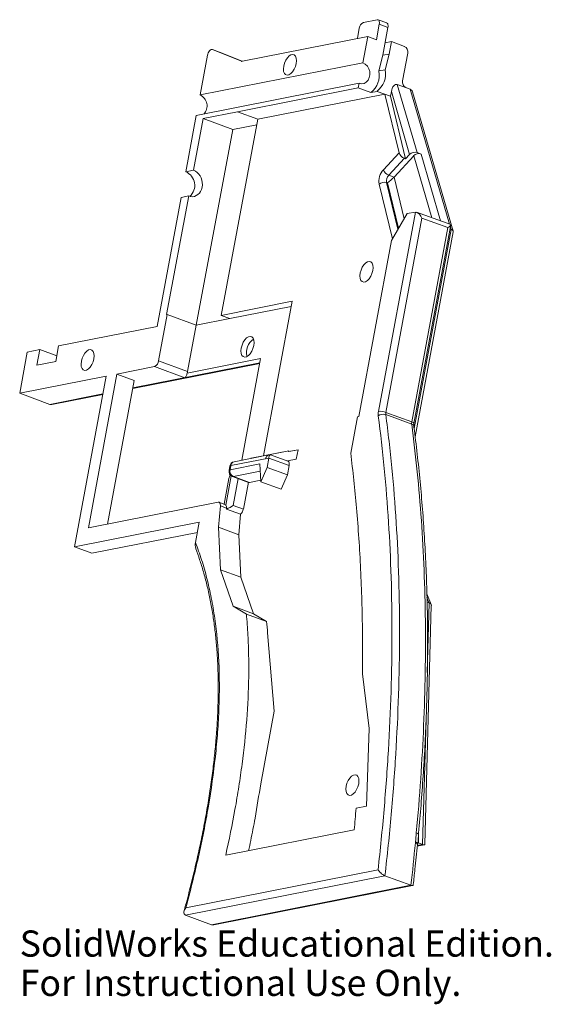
# Model space of a CAD drawing. Units: millimetres. Extents: x -5 to 93, y -110 to 72.
import ezdxf

# ---------------------------------------------------------------- set-up
doc = ezdxf.new("R2010")
doc.units = ezdxf.units.MM
doc.styles.add('SLDTEXTSTYLE0', font='TXT', dxfattribs={"width": 0.7})

msp = doc.modelspace()

# ---------------------------------------------------------------- linework, layer by layer
at = {"color": 7, "linetype": 'Continuous', "lineweight": 15}
for p, q in [((58.5, 71.07), (61.04, 71.56)), ((62.81, 70.96), (61.21, 71.55)), ((57.74, 70.01), (57.38, 68.07)), ((61.44, 70.72), (60.91, 67.87)), ((63.04, 70.13), (61.44, 70.72)), ((63.04, 70.13), (62.08, 64.99)), ((36.17, 63.88), (59.32, 68.46)), ((58.42, 63.61), (59.32, 68.46)), ((60.91, 67.87), (59.32, 68.46)), ((62.51, 67.29), (63.66, 67.51)), ((63.24, 65.22), (63.66, 67.51)), ((66.06, 66.64), (63.66, 67.51)), ((30.63, 66.04), (36, 63.9)), ((31.96, 65.55), (30.63, 66.04)), ((31.96, 65.55), (36.15, 63.88)), ((28.34, 57.67), (29.7, 64.99)), ((58.42, 63.61), (28.34, 57.67)), ((61.36, 62.1), (62.08, 64.99)), ((62.08, 64.99), (63.24, 65.22)), ((62.52, 62.32), (63.24, 65.22)), ((66.68, 65.39), (65.72, 60.26)), ((61.36, 62.1), (62.52, 62.32)), ((27.64, 53.88), (57.71, 59.82)), ((57.55, 58.96), (35.26, 54.56)), ((57.55, 58.96), (57.71, 59.82)), ((59.86, 58.11), (57.55, 58.96)), ((59.86, 58.11), (61.02, 58.34)), ((61.02, 58.34), (63.49, 57.43)), ((63.66, 58.31), (63.49, 57.43)), ((67.04, 46.71), (63.66, 58.31)), ((64.75, 59.6), (67.14, 58.73)), ((64.75, 59.6), (68.42, 47.04)), ((74.42, 33.81), (67.14, 58.73)), ((75.07, 32.56), (67.56, 58.26)), ((62.46, 57.81), (39.01, 53.18)), ((65.09, 47.01), (62.46, 57.81)), ((63.49, 57.43), (66.3, 45.9)), ((28.92, 53.31), (35.26, 54.56)), ((35.26, 54.56), (39.01, 53.18)), ((25.71, 43.49), (27.64, 53.88)), ((28.92, 53.31), (27.14, 43.77)), ((34.39, 51.31), (28.92, 53.31)), ((39.01, 53.18), (32.26, 17)), ((27.66, 15.2), (34.39, 51.31)), ((34.39, 51.31), (38.82, 52.17)), ((62.2, 43.88), (65.09, 47.01)), ((66.06, 45.99), (63.18, 42.86)), ((64.15, 42.51), (67.78, 46.44)), ((66.06, 45.99), (66.3, 45.9)), ((67.04, 46.71), (66.3, 45.9)), ((71.11, 35.02), (67.78, 46.44)), ((68.42, 47.04), (69.15, 46.77)), ((69.15, 46.77), (72.76, 34.42)), ((27.14, 43.77), (25.71, 43.49)), ((63.18, 42.86), (64.15, 42.51)), ((64.15, 42.51), (66.03, 34.81)), ((63.85, 31.13), (61.4, 41.18)), ((62.95, 41.45), (62.78, 41.52)), ((62.78, 41.52), (64.88, 32.88)), ((65, 33.07), (62.95, 41.45)), ((20.4, 14.95), (24.83, 38.74)), ((26.25, 39.03), (22.17, 17.14)), ((24.83, 38.74), (26.25, 39.03)), ((61.26, -0.72), (68.1, 36.07)), ((69.3, 34.95), (62.64, -0.9)), ((63.67, 30.82), (66.6, 35.78)), ((66.6, 35.78), (68.1, 36.07)), ((74.61, 33.74), (68.31, 36.05)), ((74.09, 33.19), (69.3, 34.95)), ((67.42, -2.66), (74.09, 33.19)), ((67.83, -2.96), (74.64, 33.69)), ((67.86, -3.9), (74.69, 32.87)), ((74.69, 32.87), (74.5, 32.94)), ((74.69, 32.87), (74.57, 33.3)), ((68.04, -5.39), (75.07, 32.44)), ((63.67, 30.82), (57.63, -1.66)), ((32.26, 17), (45.34, 19.59)), ((33.87, 16.41), (45.16, 18.64)), ((45.34, 19.59), (40.04, -8.9)), ((22.29, 17.16), (20.7, 8.61)), ((22.17, 17.14), (22.29, 17.16)), ((27.65, 15.2), (22.29, 17.16)), ((33.87, 16.41), (27.65, 15.2)), ((32.26, 17), (33.87, 16.41)), ((2.23, 11.36), (20.4, 14.95)), ((27.65, 15.2), (26.06, 6.64)), ((1.7, 8.51), (2.23, 11.36)), ((-4.95, 2.62), (-3.54, 10.22)), ((-3.54, 10.22), (-1.23, 10.67)), ((-1.76, 7.83), (-1.23, 10.67)), ((1.89, 9.53), (-1.23, 10.67)), ((1.7, 8.51), (-1.76, 7.83)), ((19.95, 7.54), (13.01, 6.17)), ((15.92, 3.49), (39.37, 8.12)), ((15.94, 3.6), (39.39, 8.23)), ((25.53, 5.49), (19.95, 7.54)), ((20.7, 8.61), (26.06, 6.64)), ((25.98, 6.35), (39.53, 9.02)), ((39.53, 9.02), (36.05, -9.74)), ((11.03, 5.78), (-4.95, 2.62)), ((11.03, 5.78), (5.17, -25.73)), ((7.73, -22.21), (13.01, 6.17)), ((16.2, 5), (13.01, 6.17)), ((11.27, -21.51), (16.2, 5)), ((-4.95, 2.62), (0.63, 0.58)), ((0.63, 0.58), (10.42, 2.51)), ((1, 0.54), (10.4, 2.4)), ((56.15, -8.42), (57.4, -1.71)), ((57.4, -1.71), (57.63, -1.66)), ((67.41, -3.08), (62.62, -1.32)), ((62.64, -0.9), (67.42, -2.66)), ((41.31, -8.7), (34.64, -10.02)), ((44.73, -7.99), (37.76, -9.36)), ((40.04, -8.9), (44.73, -7.97)), ((40.07, -8.91), (40.04, -8.9)), ((44.55, -9.88), (41.35, -8.71)), ((44.7, -8.13), (46.43, -7.79)), ((44.73, -7.97), (44.7, -8.13)), ((44.7, -8.13), (44.73, -8.14)), ((46.43, -7.8), (44.73, -8.14)), ((46.43, -7.79), (46.11, -9.53)), ((33.85, -10.82), (33.7, -11.61)), ((33.89, -11.5), (39.4, -10.41)), ((34.03, -10.71), (33.89, -11.5)), ((41.03, -9.33), (34.03, -10.71)), ((37.75, -9.41), (37.76, -9.36)), ((39.4, -10.41), (39.58, -13.71)), ((40.71, -11.07), (41.03, -9.33)), ((44.78, -10.7), (41.03, -9.33)), ((44.78, -10.7), (44.46, -12.44)), ((46.11, -9.53), (44.47, -9.85)), ((33.08, -18.01), (34.09, -12.6)), ((39.47, -11.76), (34.51, -12.74)), ((39.58, -13.71), (40.71, -11.07)), ((40.71, -11.07), (44.46, -12.44)), ((44.46, -12.44), (43.33, -15.08)), ((32.77, -17.83), (33.65, -13.13)), ((34.34, -12.73), (37.29, -13.82)), ((35.4, -13.12), (34.48, -18.07)), ((34.51, -12.74), (37.46, -13.83)), ((36.34, -18.75), (37.26, -13.8)), ((39.56, -13.41), (37.46, -13.83)), ((39.58, -13.71), (43.33, -15.08)), ((31.67, -17.48), (7.73, -22.21)), ((32.1, -18.17), (31.74, -22.11)), ((32.93, -17.89), (31.84, -17.49)), ((33.25, -18.59), (32.1, -18.17)), ((34.48, -18.07), (36.34, -18.75)), ((33.24, -18.74), (35.83, -19.69)), ((35.83, -19.69), (35.49, -23.49)), ((5.17, -25.73), (28.2, -21.18)), ((28.2, -21.18), (27.51, -24.9)), ((8.36, -26.9), (27.85, -23.05)), ((31.74, -22.11), (32.12, -29.96)), ((35.49, -23.49), (31.74, -22.11)), ((35.49, -23.49), (35.87, -31.33)), ((8.36, -26.9), (5.17, -25.73)), ((32.12, -29.96), (34.47, -36.68)), ((35.87, -31.33), (32.12, -29.96)), ((35.87, -31.33), (38.22, -38.05)), ((71.02, -36.36), (70.23, -34.41)), ((70.65, -36.05), (70.24, -35.04)), ((70.65, -36.05), (70.26, -35.91)), ((70.3, -48.88), (70.65, -36.05)), ((34.47, -36.68), (36.89, -38.12)), ((38.22, -38.05), (34.47, -36.68)), ((36.89, -38.12), (40.63, -39.49)), ((38.22, -38.05), (40.63, -39.49)), ((69.85, -80.56), (71.04, -36.52)), ((40.81, -41.61), (42.03, -56.03)), ((59.59, -59.24), (58.32, -49.13)), ((42.03, -56.03), (39.54, -69.43)), ((69.44, -80.65), (70.07, -57.58)), ((59.06, -73.59), (59.59, -59.24)), ((57.15, -73.96), (59.06, -73.59)), ((33.08, -82.64), (56.81, -77.95)), ((68.52, -80.56), (68.67, -78.84)), ((68.7, -78.32), (68.65, -80.36)), ((68.44, -80.96), (69.74, -80.7)), ((68.45, -80.85), (69.44, -80.65)), ((68.65, -80.36), (68.53, -80.38)), ((69.44, -80.65), (68.65, -80.36)), ((25.73, -92.32), (61.21, -85.31)), ((62.48, -86.42), (25.68, -93.69)), ((62.48, -86.42), (67.27, -88.18)), ((30.47, -95.45), (67.27, -88.18)), ((30.91, -95.47), (67.57, -88.22)), ((25.68, -93.69), (30.47, -95.45))]:
    msp.add_line(p, q, dxfattribs=at)
at = {"color": 7, "linetype": 'Continuous', "lineweight": 15, "flags": 128}
for points in [[(61.44, 70.72), (61.47, 70.9), (61.47, 71.07), (61.44, 71.23), (61.4, 71.36), (61.33, 71.46), (61.25, 71.53), (61.15, 71.56), (61.04, 71.56)], [(62.81, 70.96), (62.85, 70.94), (62.93, 70.87), (62.99, 70.77), (63.04, 70.64), (63.06, 70.49), (63.06, 70.32), (63.04, 70.13)], [(30.63, 66.04), (30.51, 66.06), (30.37, 66.03), (30.23, 65.94), (30.09, 65.81), (29.96, 65.64), (29.85, 65.44), (29.76, 65.22), (29.7, 64.99)], [(46.1, 63.47), (46.15, 63.99), (46.11, 64.46), (45.97, 64.82), (45.75, 65.06), (45.46, 65.15), (45.13, 65.09), (44.79, 64.87), (44.46, 64.53), (44.17, 64.07), (43.94, 63.56), (43.79, 63.01), (43.74, 62.49), (43.78, 62.02), (43.92, 61.66), (44.15, 61.42), (44.43, 61.33), (44.76, 61.39), (45.1, 61.61), (45.43, 61.95), (45.73, 62.4), (45.95, 62.92), (46.1, 63.47)], [(58.42, 63.61), (58.85, 63.37), (59.23, 63), (59.5, 62.52), (59.66, 61.97), (59.7, 61.41), (59.59, 60.87), (59.37, 60.39), (59.04, 60.03), (58.63, 59.8), (58.18, 59.73), (57.71, 59.82)], [(63.66, 58.31), (63.73, 58.61), (63.83, 58.89), (63.95, 59.14), (64.1, 59.35), (64.26, 59.5), (64.42, 59.6), (64.59, 59.63), (64.75, 59.6)], [(26.25, 39.03), (26.61, 38.93), (26.97, 38.9), (27.32, 38.96), (27.65, 39.09), (27.96, 39.29), (28.23, 39.56), (28.45, 39.88), (28.61, 40.25), (28.72, 40.65), (28.77, 41.08), (28.75, 41.52), (28.67, 41.95), (28.53, 42.37), (28.34, 42.75), (28.09, 43.1), (27.8, 43.39), (27.48, 43.61), (27.14, 43.77)], [(74.09, 33.19), (74.25, 33.3), (74.39, 33.41), (74.5, 33.5), (74.58, 33.59), (74.63, 33.65), (74.64, 33.7), (74.62, 33.73), (74.61, 33.74)], [(74.69, 32.87), (74.82, 32.82), (74.93, 32.75), (75.01, 32.67), (75.06, 32.59), (75.08, 32.5), (75.07, 32.44)], [(57.92, 24.82), (58.07, 25.36), (58.3, 25.88), (58.59, 26.33), (58.92, 26.68), (59.26, 26.89), (59.59, 26.96), (59.88, 26.87), (60.1, 26.63), (60.24, 26.26), (60.28, 25.8), (60.23, 25.27), (60.08, 24.73), (59.86, 24.21), (59.56, 23.76), (59.23, 23.41), (58.89, 23.2), (58.56, 23.13), (58.28, 23.22), (58.05, 23.46), (57.91, 23.83), (57.87, 24.29), (57.92, 24.82)], [(38.26, 11.43), (38.11, 10.88), (37.89, 10.37), (37.6, 9.91), (37.26, 9.57), (36.92, 9.35), (36.59, 9.29), (36.31, 9.38), (36.08, 9.62), (35.95, 9.98), (35.9, 10.45), (35.95, 10.97), (36.1, 11.52), (36.33, 12.04), (36.62, 12.49), (36.95, 12.83), (37.29, 13.05), (37.62, 13.11), (37.91, 13.02), (38.13, 12.78), (38.27, 12.42), (38.31, 11.95), (38.26, 11.43)], [(8.75, 8.99), (8.8, 9.51), (8.75, 9.98), (8.61, 10.34), (8.39, 10.58), (8.11, 10.67), (7.78, 10.61), (7.43, 10.39), (7.1, 10.04), (6.81, 9.59), (6.58, 9.08), (6.44, 8.53), (6.39, 8.01), (6.43, 7.54), (6.57, 7.17), (6.79, 6.94), (7.08, 6.85), (7.41, 6.91), (7.75, 7.13), (8.08, 7.47), (8.37, 7.92), (8.6, 8.44), (8.75, 8.99)], [(67.42, -2.66), (67.57, -2.72), (67.69, -2.78), (67.77, -2.84), (67.82, -2.9), (67.83, -2.95), (67.83, -2.95)], [(41.03, -9.33), (41.07, -9.15), (41.12, -9), (41.17, -8.87), (41.22, -8.78), (41.28, -8.72), (41.33, -8.7), (41.35, -8.71)], [(44.55, -9.88), (44.59, -9.9), (44.67, -9.96), (44.74, -10.06), (44.78, -10.19), (44.81, -10.35), (44.81, -10.52), (44.78, -10.7)], [(34.51, -12.74), (34.4, -12.75), (34.34, -12.73)], [(32.1, -18.17), (32.1, -18.01), (32.09, -17.87), (32.05, -17.74), (32.01, -17.63), (31.94, -17.55), (31.86, -17.5), (31.77, -17.48), (31.67, -17.48)], [(33.24, -18.74), (33.24, -18.66), (33.25, -18.59)], [(55.32, -69.9), (55.46, -69.35), (55.69, -68.84), (55.98, -68.38), (56.31, -68.04), (56.66, -67.82), (56.99, -67.76), (57.27, -67.85), (57.49, -68.09), (57.63, -68.45), (57.68, -68.92), (57.63, -69.44), (57.48, -69.99), (57.25, -70.51), (56.96, -70.96), (56.63, -71.3), (56.29, -71.52), (55.96, -71.58), (55.67, -71.49), (55.45, -71.25), (55.31, -70.89), (55.27, -70.42), (55.32, -69.9)], [(68.27, -78.49), (68.41, -78.55), (68.53, -78.62), (68.61, -78.69), (68.66, -78.77), (68.67, -78.84)], [(68.67, -78.84), (68.67, -78.85), (68.67, -78.85)], [(68.09, -80.35), (68.24, -80.41), (68.35, -80.48), (68.44, -80.56), (68.48, -80.63), (68.49, -80.7)], [(68.49, -80.7), (68.49, -80.71), (68.49, -80.71)], [(69.44, -80.65), (69.59, -80.7), (69.7, -80.71), (69.79, -80.68), (69.84, -80.63), (69.85, -80.56)]]:
    msp.add_lwpolyline(points, dxfattribs=at)
at = {"color": 7, "linetype": 'Continuous', "lineweight": 15}
for centre, radius, start, end in [((59.03, 69.88), 1.3, 114.3207, 174.4481), ((65.59, 65.63), 1.11, 347.9067, 65.2312), ((36.11, 64.18), 0.307, 248.9836, 282.2476), ((57.38, 61.32), 4.06, 307.7792, 10.9441), ((58.53, 61.55), 4.06, 307.7792, 10.9441), ((66.81, 60.03), 1.11, 167.9067, 245.2312), ((66.89, 58.08), 0.692, 14.5049, 68.7329), ((27.43, 55.66), 2.21, 316.7825, 65.5686), ((66.65, 47.53), 1.65, 198.4734, 249.1022), ((68, 45.75), 1.36, 72.2649, 135.0045), ((68.74, 45.48), 1.36, 72.2649, 135.0045), ((64.64, 41.69), 3.28, 138.0355, 188.8764), ((63.77, 44.4), 1.65, 198.4734, 249.1022), ((24.65, 40.98), 2.72, 311.8771, 67.1266), ((64.4, 41.77), 1.64, 138.0355, 188.8764), ((57.93, 48.36), 8.54, 306.0327, 316.7622), ((62.36, 40.22), 1.36, 72.2445, 134.9842), ((67.68, 34.42), 1.7, 17.8547, 75.5888), ((39.94, 10.16), 3.01, 125.1613, 194.5574), ((19.4, 8.73), 1.31, 294.8838, 354.4888), ((24.25, 6.98), 1.84, 339.8614, 349.3684), ((0.88, 1.21), 0.681, 249.2925, 280.9552), ((63.92, -1.25), 2.71, 168.7358, 186.6273), ((62.15, -2.73), 1.48, 71.3831, 128.3354), ((61.57, -3.74), 3.03, 69.3941, 95.8018), ((63.97, -1.17), 1.35, 168.7358, 186.6273), ((68.75, -2.92), 1.35, 168.7358, 186.6273), ((67.29, -3.59), 0.529, 12.1646, 76.9421), ((41.26, -9.54), 0.811, 104.3881, 173.118), ((34.83, -11), 1, 101.1755, 169.4699), ((34.03, -10.92), 0.207, 89.2596, 151.942), ((34.84, -10.81), 0.811, 104.3881, 173.118), ((35.43, -13.46), 1.81, 146.0149, 169.5494), ((34.68, -11.79), 1, 169.4699, 249.8593), ((33.88, -11.71), 0.207, 89.2596, 151.942), ((34.97, -11.74), 1.11, 167.9067, 245.2312), ((37.39, -13.53), 0.306, 250.4364, 282.3381), ((32.82, -18.19), 0.315, 33.9789, 68.92), ((30.49, -12.18), 7.11, 292.7506, 304.1072), ((34.72, -18.49), 1.63, 312.5659, 350.6424), ((70.54, -36.55), 0.509, 3.3782, 77.1146)]:
    msp.add_arc(centre, radius, start, end, dxfattribs=at)
for points, knots in [([(25.98, 6.35), (25.9, 6.14), (25.85, 5.94), (25.76, 5.71), (25.73, 5.64), (25.64, 5.54), (25.59, 5.51), (25.53, 5.49)], [0, 0, 0, 0, 0.5, 0.5, 0.75, 0.75, 1, 1, 1, 1]), ([(61.21, -85.31), (61.63, -81.59), (61.99, -77.88), (62.63, -70.52), (62.9, -66.86), (63.54, -55.97), (63.76, -48.83), (63.78, -34.78), (63.57, -27.91), (62.93, -17.84), (62.67, -14.52), (62.03, -7.98), (61.66, -4.75), (61.23, -1.57)], [0, 0, 0, 0, 0.125, 0.125, 0.25, 0.25, 0.5, 0.5, 0.75, 0.75, 0.875, 0.875, 1, 1, 1, 1]), ([(62.62, -1.32), (63.05, -4.56), (63.43, -7.83), (64.08, -14.48), (64.35, -17.85), (64.98, -28.08), (65.19, -35.06), (65.15, -49.34), (64.92, -56.6), (64.24, -67.67), (63.96, -71.39), (63.3, -78.88), (62.91, -82.64), (62.48, -86.42)], [0, 0, 0, 0, 0.125, 0.125, 0.25, 0.25, 0.5, 0.5, 0.75, 0.75, 0.875, 0.875, 1, 1, 1, 1]), ([(68.27, -78.49), (68.58, -75.14), (68.85, -71.81), (69.3, -65.2), (69.66, -58.63), (69.86, -52.16), (69.96, -45.73), (69.97, -42.54), (69.87, -33.07), (69.62, -26.89), (68.99, -17.8), (68.73, -14.8), (68.13, -8.89), (67.79, -5.96), (67.41, -3.08)], [0, 0, 0, 0, 0.125, 0.125, 0.25, 0.375, 0.375, 0.5, 0.5, 0.75, 0.75, 0.875, 0.875, 1, 1, 1, 1]), ([(67.8, -3.48), (67.8, -3.44), (67.79, -3.33), (67.8, -3.14), (67.82, -3), (67.83, -2.96)], [0, 0, 0, 0, 0.2908085, 0.8018724, 1, 1, 1, 1]), ([(68.65, -78.85), (68.68, -78.5), (68.89, -76.46), (69.21, -72.61), (69.58, -67.32), (69.9, -61.83), (70.14, -56.3), (70.29, -50.72), (70.36, -45.21), (70.35, -39.78), (70.24, -34.43), (70.06, -29.15), (69.78, -23.92), (69.42, -18.75), (68.98, -13.64), (68.44, -8.59), (68.05, -5.21), (67.81, -3.53), (67.8, -3.48)], [0, 0, 0, 0, 0.0128112, 0.0763302, 0.1445045, 0.2127726, 0.28496, 0.3568505, 0.4284984, 0.4999215, 0.57079, 0.6417024, 0.7127331, 0.7838845, 0.8551581, 0.9265548, 0.9980748, 1, 1, 1, 1]), ([(58.32, -49.13), (58.32, -48.56), (58.33, -47.99), (58.35, -45.43), (58.34, -39.51), (58.17, -33.69), (57.9, -27.95), (57.79, -26.05), (57.53, -22.28), (57.39, -20.4), (56.93, -15.11), (56.57, -11.74), (56.15, -8.42)], [0.2946604, 0.2946604, 0.2946604, 0.2946604, 0.3125, 0.3125, 0.375, 0.5, 0.5, 0.5625, 0.5625, 0.625, 0.625, 0.7403471, 0.7403471, 0.7403471, 0.7403471]), ([(33.25, -18.59), (33.25, -18.47), (33.23, -18.36), (33.17, -18.16), (33.13, -18.07), (33.08, -18.01)], [0, 0, 0, 0, 0.5, 0.5, 1, 1, 1, 1]), ([(27.51, -24.9), (27.7, -25.43), (27.9, -25.96), (28.28, -27.04), (28.46, -27.58), (28.99, -29.24), (29.64, -31.52), (30.18, -33.91), (30.55, -35.75), (30.66, -36.38), (30.87, -37.64), (30.97, -38.28), (31.43, -41.5), (31.68, -44.16), (31.94, -49.68), (31.94, -52.52), (31.78, -56.92), (31.7, -58.41), (31.47, -61.4), (31.34, -62.9), (30.84, -67.44), (30.41, -70.5), (29.62, -75.15), (29.33, -76.7), (28.72, -79.82), (28.39, -81.37), (27.35, -86.06), (26.57, -89.19), (25.73, -92.32)], [0, 0, 0, 0, 0.03125, 0.03125, 0.0625, 0.0625, 0.125, 0.1875, 0.1875, 0.21875, 0.21875, 0.25, 0.25, 0.375, 0.375, 0.5, 0.5, 0.5625, 0.5625, 0.625, 0.625, 0.75, 0.75, 0.8125, 0.8125, 0.875, 0.875, 1, 1, 1, 1]), ([(27.58, -26.09), (27.57, -26.06), (27.48, -25.87), (27.44, -25.45), (27.48, -25.08), (27.51, -24.9)], [0, 0, 0, 0, 0.070708, 0.533932, 1, 1, 1, 1]), ([(27.58, -26.09), (27.81, -26.75), (28.3, -28.13), (28.98, -30.33), (29.62, -32.72), (30.18, -35.23), (30.65, -37.8), (31.03, -40.41), (31.33, -43.09), (31.54, -45.83), (31.67, -48.65), (31.72, -51.55), (31.68, -54.52), (31.56, -57.56), (31.36, -60.66), (31.07, -63.82), (30.7, -67.07), (30.24, -70.42), (29.69, -73.85), (29.05, -77.38), (28.31, -81), (27.48, -84.74), (26.56, -88.53), (25.85, -91.27), (25.45, -92.73), (25.39, -92.94)], [0, 0, 0, 0, 0.039005, 0.081189, 0.125977, 0.170034, 0.213713, 0.257, 0.299458, 0.342145, 0.385157, 0.428465, 0.472032, 0.515814, 0.559757, 0.603709, 0.649033, 0.695015, 0.741825, 0.789637, 0.838633, 0.889012, 0.940944, 0.99165, 1, 1, 1, 1]), ([(36.89, -38.12), (37.01, -39.4), (37.11, -40.71), (37.25, -43.29), (37.3, -44.56), (37.34, -47.13), (37.35, -48.42), (37.25, -54.94), (36.83, -60.3), (35.92, -67.18), (35.72, -68.57), (35.29, -71.35), (35.05, -72.76), (34.29, -76.98), (33.72, -79.8), (33.08, -82.64)], [0.3079561, 0.3079561, 0.3079561, 0.3079561, 0.375, 0.375, 0.4375, 0.4375, 0.5, 0.5, 0.75, 0.75, 0.8125, 0.8125, 0.875, 0.875, 1, 1, 1, 1]), ([(37.3, -81.8), (37.44, -81.17), (37.87, -79.17), (38.66, -75.03), (39.21, -71.55), (39.54, -69.43)], [0, 0, 0, 0, 0.152593, 0.482561, 1, 1, 1, 1]), ([(67.7, -88.04), (67.81, -87.1), (68.08, -84.65), (68.32, -82.22), (68.47, -80.71)], [0, 0, 0, 0, 0.380794, 1, 1, 1, 1]), ([(68.12, -80.17), (68.12, -80.18), (68.16, -80.19), (68.27, -80.24), (68.42, -80.35), (68.52, -80.48), (68.5, -80.55), (68.5, -80.58)], [0, 0, 0, 0, 0.019229, 0.122216, 0.451953, 0.781077, 1, 1, 1, 1]), ([(68.49, -80.73), (68.49, -80.7), (68.5, -80.65), (68.51, -80.6), (68.51, -80.59)], [0, 0, 0, 0, 0.566812, 1, 1, 1, 1]), ([(62.48, -86.42), (62.35, -86.38), (62.2, -86.29), (61.92, -86.1), (61.8, -86), (61.47, -85.69), (61.31, -85.49), (61.21, -85.31)], [0, 0, 0, 0, 0.25, 0.25, 0.5, 0.5, 1, 1, 1, 1]), ([(67.27, -88.18), (67.33, -88.2), (67.46, -88.24), (67.61, -88.22), (67.71, -88.16), (67.7, -88.07), (67.7, -88.04)], [0, 0, 0, 0, 0.222529, 0.443814, 0.768729, 1, 1, 1, 1]), ([(25.68, -93.69), (25.55, -93.64), (25.46, -93.55), (25.36, -93.32), (25.36, -93.2), (25.41, -92.82), (25.55, -92.56), (25.73, -92.32)], [0, 0, 0, 0, 0.25, 0.25, 0.5, 0.5, 1, 1, 1, 1]), ([(30.47, -95.45), (30.54, -95.47), (30.68, -95.5), (30.84, -95.48), (30.91, -95.46)], [0, 0, 0, 0, 0.534002, 1, 1, 1, 1])]:
    msp.add_open_spline(points, degree=3, knots=knots, dxfattribs=at)
for points in [[(40.63, -39.49), (40.7, -40.19), (40.76, -40.9), (40.81, -41.61)], [(56.81, -77.95), (56.93, -76.62), (57.04, -75.29), (57.15, -73.96)], [(68.12, -80.17), (68.17, -79.61), (68.22, -79.05), (68.27, -78.49)], [(67.27, -88.18), (67.57, -85.56), (67.84, -82.95), (68.09, -80.35)], [(68.09, -80.35), (68.1, -80.29), (68.11, -80.23), (68.12, -80.17)]]:
    msp.add_open_spline(points, degree=3, dxfattribs=at)

# ---------------------------------------------------------------- texts
at = {"color": 7, "linetype": 'Continuous', "char_height": 4.8336, "attachment_point": 1, "style": 'SLDTEXTSTYLE0'}
for s, insert in [('SolidWorks Educational Edition.', (-4.95, -96.51)), ('For Instructional Use Only.', (-4.95, -103.76))]:
    msp.add_mtext(s, dxfattribs=dict(at, insert=insert))

doc.saveas('drawing.dxf')
